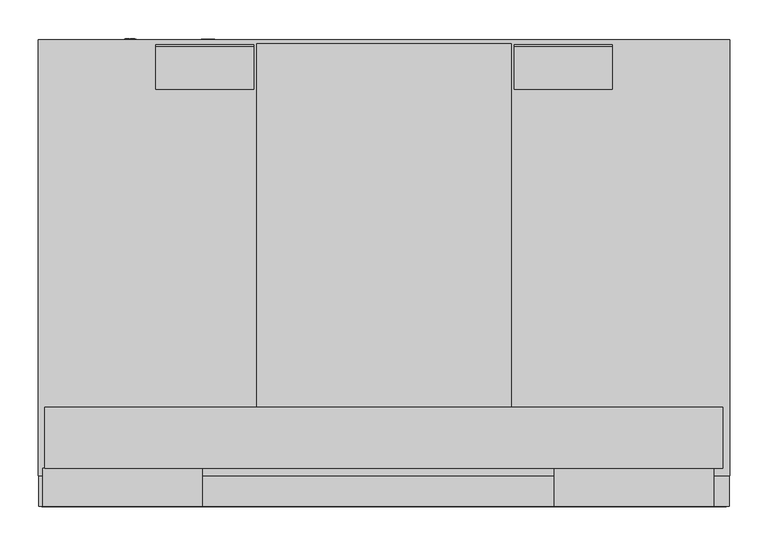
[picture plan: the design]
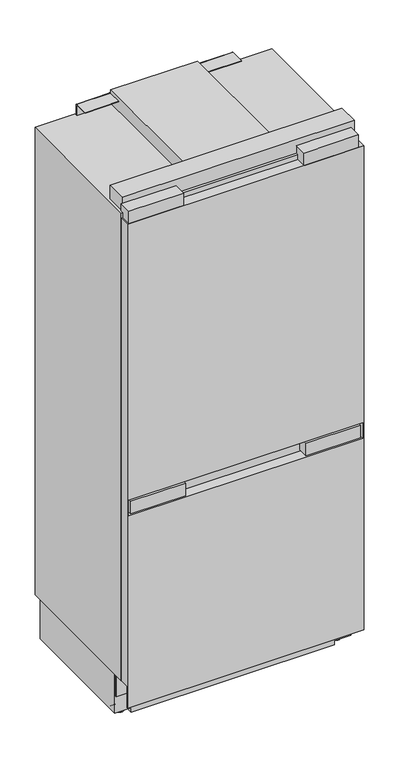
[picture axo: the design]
"""IFC4 building model written with IfcOpenShell, lengths in millimetres: proxy geometry."""

from ifc_helpers import new_model, si_unit, point, frame, frame_2d, origin, place, context, project, spatial, polyline, circle_curve, trimmed, segment, composite_curve, outline, extrude, faceted_brep, source, transform, mapped, element, save
from ifc_brep_helpers import plane_surface, cylinder_surface, advanced_brep


def specialty_equipment_2ae30996(model_context):
    return source(origin(), model_context, "Body", "SolidModel", [
        faceted_brep([(450.5, 19.5805006, 2048.9273907), (450.5, 19.5805006, 100.0958717), (450.5, 22.474204, 100.0958717), (450.5, 22.474204, 187.4499998), (450.5, 95.0, 187.4499998), (450.5, 95.0, 100.0958717), (450.5, 99.0001378, 100.0958717), (450.5, 99.0001378, 2048.9273907), (-450.5, 19.5805006, 2048.9273907), (-450.5, 99.0001378, 2048.9273907), (-450.5, 99.0001378, 100.0958717), (-450.5, 95.0, 100.0958717), (-450.5, 95.0, 187.4499998), (-450.5, 22.474204, 187.4499998), (-450.5, 22.474204, 100.0958717), (-450.5, 19.5805006, 100.0958717), (-446.5, 19.5805006, 934.8801375), (446.5, 19.5805006, 934.8801375), (446.5, 19.5805006, 872.4), (-446.5, 19.5805006, 872.4), (446.5, 93.7083842, 934.8801375), (-446.5, 93.7083842, 934.8801375), (-446.5, 93.7083842, 872.4), (446.5, 93.7083842, 872.4)], [[[0, 1, 2, 3, 4, 5, 6, 7]], [[8, 9, 10, 11, 12, 13, 14, 15]], [[1, 0, 8, 15], [16, 17, 18, 19]], [[1, 15, 14, 2]], [[10, 6, 5, 11]], [[7, 6, 10, 9]], [[0, 7, 9, 8]], [[13, 3, 2, 14]], [[4, 12, 11, 5]], [[3, 13, 12, 4]], [[20, 21, 22, 23]], [[21, 20, 17, 16]], [[22, 21, 16, 19]], [[23, 22, 19, 18]], [[20, 23, 18, 17]]]),
        extrude(outline(polyline([(-229.8997253, 19.5805006), (-437.799475, 19.5805006), (-437.799475, 69.0), (-229.8997253, 69.0), (-229.8997253, 19.5805006)])), frame((0.0, 0.0, 878.4), z_axis=(0.0, 0.0, 1.0), x_axis=(1.0, 0.0, 0.0)), (0.0, 0.0, 1.0), 50.4801375),
        extrude(outline(polyline([(437.799475, 19.5805006), (229.8997253, 19.5805006), (229.8997253, 69.0), (437.799475, 69.0), (437.799475, 19.5805006)])), frame((0.0, 0.0, 878.4), z_axis=(0.0, 0.0, 1.0), x_axis=(1.0, 0.0, 0.0)), (0.0, 0.0, 1.0), 50.4801375),
        extrude(outline(polyline([(-237.4494506, 19.5805006), (-445.3492003, 19.5805006), (-445.3492003, 69.0), (-237.4494506, 69.0), (-237.4494506, 19.5805006)])), frame((0.0, 0.0, 2048.9273907), z_axis=(0.0, 0.0, 1.0), x_axis=(1.0, 0.0, 0.0)), (0.0, 0.0, 1.0), 50.4801375),
        extrude(outline(polyline([(430.2497498, 19.5805006), (222.35, 19.5805006), (222.35, 69.0), (430.2497498, 69.0), (430.2497498, 19.5805006)])), frame((0.0, 0.0, 2048.9273907), z_axis=(0.0, 0.0, 1.0), x_axis=(1.0, 0.0, 0.0)), (0.0, 0.0, 1.0), 50.4801375),
        extrude(outline(composite_curve([segment(trimmed(circle_curve(frame_2d((619.3046941, 2111.8999939)), 2.5), [point((619.3046941, 2114.3999939))], [point((621.8046941, 2111.8999939))], False, "CARTESIAN"), True, "CONTINUOUS"), segment(polyline([(621.8046941, 2111.8999939), (621.8046941, 2068.8999998), (619.3046941, 2068.8999998), (619.3046941, 2112.2000427), (563.7854458, 2112.2000427), (563.7854458, 2114.3999939), (619.3046941, 2114.3999939)]), True, "CONTINUOUS")], self_intersect=False)), frame((170.0666274, 0.0, 0.0), z_axis=(1.0, 0.0, 0.0), x_axis=(0.0, 1.0, 0.0)), (0.0, 0.0, 1.0), 127.807223),
        extrude(outline(composite_curve([segment(trimmed(circle_curve(frame_2d((619.3046941, 2111.8999939)), 2.5), [point((619.3046941, 2114.3999939))], [point((621.8046941, 2111.8999939))], False, "CARTESIAN"), True, "CONTINUOUS"), segment(polyline([(621.8046941, 2111.8999939), (621.8046941, 2068.8999998), (619.3046941, 2068.8999998), (619.3046941, 2112.2000427), (563.7854458, 2112.2000427), (563.7854458, 2114.3999939), (619.3046941, 2114.3999939)]), True, "CONTINUOUS")], self_intersect=False)), frame((-297.8738504, 0.0, 0.0), z_axis=(1.0, 0.0, 0.0), x_axis=(0.0, 1.0, 0.0)), (0.0, 0.0, 1.0), 127.807223),
        faceted_brep([(451.0, 628.6068181, 2068.8999998), (-451.0, 628.6068181, 2068.8999998), (-451.0, 59.5250826, 2068.8999998), (451.0, 59.5250826, 2068.8999998), (451.0, 628.6068181, 187.4499998), (451.0, 59.5250826, 187.4499998), (-451.0, 59.5250826, 187.4499998), (-451.0, 628.6068181, 187.4499998), (-402.0265198, 59.5250826, 1999.0), (402.0265198, 59.5250826, 1999.0), (402.0265198, 59.5250826, 920.0), (-402.0265198, 59.5250826, 920.0), (-402.0265198, 59.5250826, 777.0), (402.0265198, 59.5250826, 777.0), (402.0265198, 59.5250826, 250.0), (-402.0265198, 59.5250826, 250.0), (402.0265198, 551.4500008, 1999.0), (-402.0265198, 551.4500008, 1999.0), (-402.0265198, 551.4500008, 920.0), (402.0265198, 551.4500008, 920.0), (402.0265198, 535.9500008, 777.0), (-402.0265198, 535.9500008, 777.0), (-402.0265198, 535.9500008, 250.0), (402.0265198, 535.9500008, 250.0)], [[[0, 1, 2, 3]], [[4, 5, 6, 7]], [[0, 3, 5, 4]], [[3, 2, 6, 5], [8, 9, 10, 11], [12, 13, 14, 15]], [[2, 1, 7, 6]], [[1, 0, 4, 7]], [[16, 17, 18, 19]], [[17, 16, 9, 8]], [[18, 17, 8, 11]], [[19, 18, 11, 10]], [[16, 19, 10, 9]], [[20, 21, 22, 23]], [[21, 20, 13, 12]], [[22, 21, 12, 15]], [[23, 22, 15, 14]], [[20, 23, 14, 13]]]),
        advanced_brep(
        [(-449.5, 599.2160102, 187.4499998), (449.5, 599.2160102, 187.4499998), (449.5, 599.2160102, 27.500001), (387.3898346, 599.2160102, 27.500001), (387.3898346, 599.2160102, 10.4), (-387.3898346, 599.2160102, 10.4), (-387.3898346, 599.2160102, 27.500001), (-449.5, 599.2160102, 27.500001), (449.5, 104.7548719, 187.4499998), (-449.5, 104.7548719, 187.4499998), (-449.5, 104.7548719, 27.500001), (-387.3898346, 104.7548719, 27.500001), (-387.3898346, 104.7548719, 10.4), (387.3898346, 104.7548719, 10.4), (387.3898346, 104.7548719, 27.500001), (449.5, 104.7548719, 27.500001), (-406.4950732, 165.898232, 25.006546), (-406.4950732, 215.911324, 25.006546), (-406.4950732, 215.7866997, 27.500001), (-406.4950732, 166.0228563, 27.500001), (-406.4950732, 488.6286933, 25.006546), (-406.4950732, 538.6417854, 25.006546), (-406.4950732, 538.517161, 27.500001), (-406.4950732, 488.7533177, 27.500001), (-424.0, 215.911324, 25.006546), (-424.0, 165.898232, 25.006546), (-424.0, 166.0228563, 27.500001), (-424.0, 215.7866997, 27.500001), (-424.0, 538.6417854, 25.006546), (-424.0, 488.6286933, 25.006546), (-424.0, 488.7533177, 27.500001), (-424.0, 538.517161, 27.500001), (424.0, 165.898139, 25.006546), (424.0, 215.911231, 25.006546), (424.0, 215.7866067, 27.500001), (424.0, 166.0227633, 27.500001), (424.0, 488.6286933, 25.006546), (424.0, 538.6417854, 25.006546), (424.0, 538.517161, 27.500001), (424.0, 488.7533177, 27.500001), (406.4950732, 215.911231, 25.006546), (406.4950732, 165.898139, 25.006546), (406.4950732, 166.0227633, 27.500001), (406.4950732, 215.7866067, 27.500001), (406.4950732, 538.6417854, 25.006546), (406.4950732, 488.6286933, 25.006546), (406.4950732, 488.7533177, 27.500001), (406.4950732, 538.517161, 27.500001)],
        [
            (0, 1),
            (1, 2),
            (2, 3),
            (3, 4),
            (4, 5),
            (5, 6),
            (6, 7),
            (7, 0),
            (8, 9),
            (9, 10),
            (10, 11),
            (11, 12),
            (12, 13),
            (13, 14),
            (14, 15),
            (15, 8),
            (0, 9),
            (8, 1),
            (7, 10),
            (4, 13),
            (12, 5),
            (15, 2),
            (16, 17, circle_curve(frame((-406.4950732, 190.904778, 25.006546), z_axis=(1.0, 0.0, 0.0), x_axis=(0.0, 1.0, 0.0)), 25.006546)),
            (17, 18, circle_curve(frame((-406.4950732, 190.904778, 25.006546), z_axis=(1.0, 0.0, 0.0), x_axis=(0.0, 1.0, 0.0)), 25.006546)),
            (18, 19),
            (19, 16, circle_curve(frame((-406.4950732, 190.904778, 25.006546), z_axis=(1.0, 0.0, 0.0), x_axis=(0.0, 1.0, 0.0)), 25.006546)),
            (20, 21, circle_curve(frame((-406.4950732, 513.6352393, 25.006546), z_axis=(1.0, 0.0, 0.0), x_axis=(0.0, 1.0, 0.0)), 25.006546)),
            (21, 22, circle_curve(frame((-406.4950732, 513.6352393, 25.006546), z_axis=(1.0, 0.0, 0.0), x_axis=(0.0, 1.0, 0.0)), 25.006546)),
            (22, 23),
            (23, 20, circle_curve(frame((-406.4950732, 513.6352393, 25.006546), z_axis=(1.0, 0.0, 0.0), x_axis=(0.0, 1.0, 0.0)), 25.006546)),
            (24, 25, circle_curve(frame((-424.0, 190.904778, 25.006546), z_axis=(-1.0, 0.0, 0.0), x_axis=(0.0, 1.0, 0.0)), 25.006546)),
            (25, 26, circle_curve(frame((-424.0, 190.904778, 25.006546), z_axis=(-1.0, 0.0, 0.0), x_axis=(0.0, 1.0, 0.0)), 25.006546)),
            (26, 27),
            (27, 24, circle_curve(frame((-424.0, 190.904778, 25.006546), z_axis=(-1.0, 0.0, 0.0), x_axis=(0.0, 1.0, 0.0)), 25.006546)),
            (28, 29, circle_curve(frame((-424.0, 513.6352393, 25.006546), z_axis=(-1.0, 0.0, 0.0), x_axis=(0.0, 1.0, 0.0)), 25.006546)),
            (29, 30, circle_curve(frame((-424.0, 513.6352393, 25.006546), z_axis=(-1.0, 0.0, 0.0), x_axis=(0.0, 1.0, 0.0)), 25.006546)),
            (30, 31),
            (31, 28, circle_curve(frame((-424.0, 513.6352393, 25.006546), z_axis=(-1.0, 0.0, 0.0), x_axis=(0.0, 1.0, 0.0)), 25.006546)),
            (16, 25),
            (24, 17),
            (20, 29),
            (28, 21),
            (32, 33, circle_curve(frame((424.0, 190.904685, 25.006546), z_axis=(1.0, 0.0, 0.0), x_axis=(0.0, 1.0, 0.0)), 25.006546)),
            (33, 34, circle_curve(frame((424.0, 190.904685, 25.006546), z_axis=(1.0, 0.0, 0.0), x_axis=(0.0, 1.0, 0.0)), 25.006546)),
            (34, 35),
            (35, 32, circle_curve(frame((424.0, 190.904685, 25.006546), z_axis=(1.0, 0.0, 0.0), x_axis=(0.0, 1.0, 0.0)), 25.006546)),
            (36, 37, circle_curve(frame((424.0, 513.6352393, 25.006546), z_axis=(1.0, 0.0, 0.0), x_axis=(0.0, 1.0, 0.0)), 25.006546)),
            (37, 38, circle_curve(frame((424.0, 513.6352393, 25.006546), z_axis=(1.0, 0.0, 0.0), x_axis=(0.0, 1.0, 0.0)), 25.006546)),
            (38, 39),
            (39, 36, circle_curve(frame((424.0, 513.6352393, 25.006546), z_axis=(1.0, 0.0, 0.0), x_axis=(0.0, 1.0, 0.0)), 25.006546)),
            (40, 41, circle_curve(frame((406.4950732, 190.904685, 25.006546), z_axis=(-1.0, 0.0, 0.0), x_axis=(0.0, 1.0, 0.0)), 25.006546)),
            (41, 42, circle_curve(frame((406.4950732, 190.904685, 25.006546), z_axis=(-1.0, 0.0, 0.0), x_axis=(0.0, 1.0, 0.0)), 25.006546)),
            (42, 43),
            (43, 40, circle_curve(frame((406.4950732, 190.904685, 25.006546), z_axis=(-1.0, 0.0, 0.0), x_axis=(0.0, 1.0, 0.0)), 25.006546)),
            (44, 45, circle_curve(frame((406.4950732, 513.6352393, 25.006546), z_axis=(-1.0, 0.0, 0.0), x_axis=(0.0, 1.0, 0.0)), 25.006546)),
            (45, 46, circle_curve(frame((406.4950732, 513.6352393, 25.006546), z_axis=(-1.0, 0.0, 0.0), x_axis=(0.0, 1.0, 0.0)), 25.006546)),
            (46, 47),
            (47, 44, circle_curve(frame((406.4950732, 513.6352393, 25.006546), z_axis=(-1.0, 0.0, 0.0), x_axis=(0.0, 1.0, 0.0)), 25.006546)),
            (32, 41),
            (40, 33),
            (36, 45),
            (44, 37),
            (19, 26),
            (27, 18),
            (23, 30),
            (31, 22),
            (43, 34),
            (35, 42),
            (47, 38),
            (39, 46),
            (11, 6),
            (14, 3),
        ],
        [
            plane_surface(frame((-449.5, 599.2160102, 187.4499998), z_axis=(0.0, 1.0, 0.0), x_axis=(1.0, 0.0, 0.0))),
            plane_surface(frame((-449.5, 104.7548719, 187.4499998), z_axis=(0.0, -1.0, 0.0), x_axis=(-1.0, 0.0, 0.0))),
            plane_surface(frame((449.5, 104.7548719, 187.4499998), z_axis=(0.0, 0.0, 1.0), x_axis=(0.0, 1.0, 0.0))),
            plane_surface(frame((-449.5, 104.7548719, 187.4499998), z_axis=(-1.0, 0.0, 0.0), x_axis=(0.0, 1.0, 0.0))),
            plane_surface(frame((-449.5, 104.7548719, 10.4), z_axis=(0.0, 0.0, -1.0), x_axis=(0.0, 1.0, 0.0))),
            plane_surface(frame((449.5, 104.7548719, 10.4), z_axis=(1.0, 0.0, 0.0), x_axis=(0.0, 1.0, 0.0))),
            plane_surface(frame((-406.4950732, 215.911324, 25.006546), z_axis=(1.0, 0.0, 0.0), x_axis=(0.0, 0.0, 1.0))),
            plane_surface(frame((-424.0, 215.911324, 25.006546), z_axis=(-1.0, 0.0, 0.0), x_axis=(0.0, 0.0, -1.0))),
            cylinder_surface(frame((-424.0, 190.904778, 25.006546), z_axis=(1.0, 0.0, 0.0), x_axis=(0.0, 1.0, 0.0)), 25.006546),
            cylinder_surface(frame((0.0, 513.6352393, 25.006546), z_axis=(1.0, 0.0, 0.0), x_axis=(0.0, 1.0, 0.0)), 25.006546),
            plane_surface(frame((424.0, 215.911231, 25.006546), z_axis=(1.0, 0.0, 0.0), x_axis=(0.0, 0.0, 1.0))),
            plane_surface(frame((406.4950732, 215.911231, 25.006546), z_axis=(-1.0, 0.0, 0.0), x_axis=(0.0, 0.0, -1.0))),
            cylinder_surface(frame((424.0, 190.904685, 25.006546), z_axis=(-1.0, 0.0, 0.0), x_axis=(0.0, 1.0, 0.0)), 25.006546),
            cylinder_surface(frame((0.0, 513.6352393, 25.006546), z_axis=(-1.0, 0.0, 0.0), x_axis=(0.0, 1.0, 0.0)), 25.006546),
            plane_surface(frame((-387.3898346, -429.4357797, 0.0), z_axis=(-1.0, 0.0, 0.0), x_axis=(0.0, 1.0, 0.0))),
            plane_surface(frame((-387.3898346, -429.4357797, 27.500001), z_axis=(0.0, 0.0, -1.0), x_axis=(0.0, 1.0, 0.0))),
            plane_surface(frame((451.0, -429.4357797, 27.500001), z_axis=(0.0, 0.0, -1.0), x_axis=(0.0, 1.0, 0.0))),
            plane_surface(frame((387.3898346, -429.4357797, 27.500001), z_axis=(1.0, 0.0, 0.0), x_axis=(0.0, 1.0, 0.0))),
        ],
        [
            (0, [[1, 2, 3, 4, 5, 6, 7, 8]]),
            (1, [[9, 10, 11, 12, 13, 14, 15, 16]]),
            (2, [[-1, 17, -9, 18]]),
            (3, [[-17, -8, 19, -10]]),
            (4, [[-5, 20, -13, 21]]),
            (5, [[-18, -16, 22, -2]]),
            (6, [[23, 24, 25, 26]]),
            (6, [[27, 28, 29, 30]]),
            (7, [[31, 32, 33, 34]]),
            (7, [[35, 36, 37, 38]]),
            (8, [[-23, 39, -31, 40]]),
            (9, [[-27, 41, -35, 42]]),
            (10, [[43, 44, 45, 46]]),
            (10, [[47, 48, 49, 50]]),
            (11, [[51, 52, 53, 54]]),
            (11, [[55, 56, 57, 58]]),
            (12, [[-43, 59, -51, 60]]),
            (13, [[-47, 61, -55, 62]]),
            (8, [[-39, -26, 63, -32]]),
            (8, [[-40, -34, 64, -24]]),
            (9, [[-41, -30, 65, -36]]),
            (9, [[-42, -38, 66, -28]]),
            (12, [[-60, -54, 67, -44]]),
            (12, [[-59, -46, 68, -52]]),
            (13, [[-62, -58, 69, -48]]),
            (13, [[-61, -50, 70, -56]]),
            (14, [[71, -6, -21, -12]]),
            (15, [[-71, -11, -19, -7], [-25, -64, -33, -63], [-29, -66, -37, -65]]),
            (16, [[72, -3, -22, -15], [-45, -67, -53, -68], [-49, -69, -57, -70]]),
            (17, [[-72, -14, -20, -4]]),
        ],
    ),
        extrude(outline(composite_curve([segment(trimmed(circle_curve(frame_2d((-413.6, 136.7)), 15.0), [point((-428.6, 136.7))], [point((-398.6, 136.7))], False, "CARTESIAN"), True, "CONTINUOUS"), segment(trimmed(circle_curve(frame_2d((-413.6, 136.7)), 15.0), [point((-398.6, 136.7))], [point((-428.6, 136.7))], False, "CARTESIAN"), True, "CONTINUOUS")], self_intersect=False)), frame((0.0, 0.0, 10.4), z_axis=(0.0, 0.0, 1.0), x_axis=(1.0, 0.0, 0.0)), (0.0, 0.0, 1.0), 3.4999939),
        extrude(outline(composite_curve([segment(trimmed(circle_curve(frame_2d((413.6, 136.7)), 15.0), [point((398.6, 136.7))], [point((428.6, 136.7))], False, "CARTESIAN"), True, "CONTINUOUS"), segment(trimmed(circle_curve(frame_2d((413.6, 136.7)), 15.0), [point((428.6, 136.7))], [point((398.6, 136.7))], False, "CARTESIAN"), True, "CONTINUOUS")], self_intersect=False)), frame((0.0, 0.0, 10.4), z_axis=(0.0, 0.0, 1.0), x_axis=(1.0, 0.0, 0.0)), (0.0, 0.0, 1.0), 3.4999939),
        extrude(outline(composite_curve([segment(trimmed(circle_curve(frame_2d((413.6, 136.7)), 10.0), [point((403.6, 136.7))], [point((423.6, 136.7))], False, "CARTESIAN"), True, "CONTINUOUS"), segment(trimmed(circle_curve(frame_2d((413.6, 136.7)), 10.0), [point((423.6, 136.7))], [point((403.6, 136.7))], False, "CARTESIAN"), True, "CONTINUOUS")], self_intersect=False)), frame((0.0, 0.0, 13.8999939), z_axis=(0.0, 0.0, 1.0), x_axis=(1.0, 0.0, 0.0)), (0.0, 0.0, 1.0), 13.6000071),
        extrude(outline(composite_curve([segment(trimmed(circle_curve(frame_2d((-413.6, 136.7)), 10.0), [point((-423.6, 136.7))], [point((-403.6, 136.7))], False, "CARTESIAN"), True, "CONTINUOUS"), segment(trimmed(circle_curve(frame_2d((-413.6, 136.7)), 10.0), [point((-403.6, 136.7))], [point((-423.6, 136.7))], False, "CARTESIAN"), True, "CONTINUOUS")], self_intersect=False)), frame((0.0, 0.0, 13.8999939), z_axis=(0.0, 0.0, 1.0), x_axis=(1.0, 0.0, 0.0)), (0.0, 0.0, 1.0), 13.6000071),
        faceted_brep([(166.0, 623.4547186, 2122.8999939), (-166.0, 623.4547186, 2122.8999939), (-166.0, 149.0, 2122.8999939), (166.0, 149.0, 2122.8999939), (-166.0, 623.4547186, 2068.8999998), (166.0, 623.4547186, 2068.8999998), (166.0, 149.0, 2068.8999998), (442.1341127, 149.0, 2068.8999998), (442.1341127, 69.0, 2068.8999998), (-442.7652816, 69.0, 2068.8999998), (-442.7652816, 149.0, 2068.8999998), (-166.0, 149.0, 2068.8999998), (442.1341127, 69.0, 2124.5509637), (442.1341127, 149.0, 2124.5509637), (-442.7652816, 69.0, 2124.5509637), (-442.7652816, 149.0, 2124.5509637)], [[[0, 1, 2, 3]], [[4, 5, 6, 7, 8, 9, 10, 11]], [[5, 0, 3, 6]], [[1, 0, 5, 4]], [[1, 4, 11, 2]], [[12, 8, 7, 13]], [[14, 15, 10, 9]], [[8, 12, 14, 9]], [[13, 7, 6, 3, 2, 11, 10, 15]], [[12, 13, 15, 14]]]),
        extrude(outline(composite_curve([segment(trimmed(circle_curve(frame_2d((68.8909912, -331.0)), 8.0), [point((68.8909912, -339.0))], [point((68.8909912, -323.0))], False, "CARTESIAN"), True, "CONTINUOUS"), segment(trimmed(circle_curve(frame_2d((68.8909912, -331.0)), 8.0), [point((68.8909912, -323.0))], [point((68.8909912, -339.0))], False, "CARTESIAN"), True, "CONTINUOUS")], self_intersect=False)), frame((0.0, 599.2160102, 0.0), z_axis=(0.0, 1.0, 0.0), x_axis=(0.0, 0.0, 1.0)), (0.0, 0.0, 1.0), 30.0),
        extrude(outline(polyline([(64.7404068, -325.0981918), (72.7769116, -325.0981918), (72.7769116, -330.8744296), (71.7723485, -330.8744296), (71.7723485, -326.1027549), (69.3865111, -326.1027549), (69.3865111, -330.6232888), (68.381948, -330.6232888), (68.381948, -326.1027549), (65.7449699, -326.1027549), (65.7449699, -331.0), (64.7404068, -331.0), (64.7404068, -325.0981918)])), frame((0.0, 629.2160102, 0.0), z_axis=(0.0, 1.0, 0.0), x_axis=(0.0, 0.0, 1.0)), (0.0, 0.0, 1.0), 1.0),
        extrude(outline(polyline([(64.7404068, -332.5068447), (72.7769116, -332.5068447), (72.7769116, -333.5114078), (65.7449699, -333.5114078), (65.7449699, -337.5296602), (64.7404068, -337.5296602), (64.7404068, -332.5068447)])), frame((0.0, 629.2160102, 0.0), z_axis=(0.0, 1.0, 0.0), x_axis=(0.0, 0.0, 1.0)), (0.0, 0.0, 1.0), 1.0),
        extrude(outline(composite_curve([segment(trimmed(circle_curve(frame_2d((38.8909912, -229.0)), 8.0), [point((38.8909912, -237.0))], [point((38.8909912, -221.0))], False, "CARTESIAN"), True, "CONTINUOUS"), segment(trimmed(circle_curve(frame_2d((38.8909912, -229.0)), 8.0), [point((38.8909912, -221.0))], [point((38.8909912, -237.0))], False, "CARTESIAN"), True, "CONTINUOUS")], self_intersect=False)), frame((0.0, 599.2160102, 0.0), z_axis=(0.0, 1.0, 0.0), x_axis=(0.0, 0.0, 1.0)), (0.0, 0.0, 1.0), 30.0),
        extrude(outline(polyline([(35.5144425, -229.9875487), (43.5509473, -227.795953), (43.5509473, -228.8319087), (38.2691429, -230.1033089), (36.6386899, -230.4957164), (38.0807873, -230.9155923), (43.5509473, -232.5087666), (43.5509473, -234.001877), (39.5856699, -235.159479), (36.6386899, -236.0208134), (38.222054, -236.4014486), (43.5509473, -237.682659), (43.5509473, -238.7205767), (35.5144425, -236.5309431), (35.5144425, -235.4557467), (41.7144804, -233.527064), (42.5797389, -233.2582649), (41.5378971, -232.9561111), (35.5144425, -231.2000877), (35.5144425, -229.9875487)])), frame((0.0, 628.6068181, 0.0), z_axis=(0.0, 1.0, 0.0), x_axis=(0.0, 0.0, 1.0)), (0.0, 0.0, 1.0), 1.0),
        extrude(outline(polyline([(35.5144425, -221.1407225), (43.5509473, -221.1407225), (43.5509473, -222.1452856), (39.6170625, -222.1452856), (43.5509473, -226.2655639), (43.5509473, -227.6703826), (40.2468765, -224.2093488), (35.5144425, -227.795953), (35.5144425, -226.5677177), (39.5680116, -223.4971293), (38.2769911, -222.1452856), (35.5144425, -222.1452856), (35.5144425, -221.1407225)])), frame((0.0, 628.6068181, 0.0), z_axis=(0.0, 1.0, 0.0), x_axis=(0.0, 0.0, 1.0)), (0.0, 0.0, 1.0), 1.0),
    ])


if __name__ == "__main__":
    model = new_model("IFC4")
    model_context = context("Model", 3, world=origin())
    ifc_project = project(units=[si_unit("LENGTHUNIT", "METRE", prefix="MILLI")], contexts=[model_context])
    site = spatial("IfcSite", under=ifc_project)
    building = spatial("IfcBuilding", under=site)
    placement = place(None, origin())
    specialty_equipment_shape = specialty_equipment_2ae30996(model_context)
    element("IfcBuildingElementProxy", 1, Name="Specialty Equipment", at=placement, inside=building, context=model_context, shape_type="MappedRepresentation", body=[
        mapped(specialty_equipment_shape, transform((0.0, 0.0, 0.0), x_axis=(1.0, 0.0, 0.0), y_axis=(0.0, 1.0, 0.0), z_axis=(0.0, 0.0, 1.0))),
    ])
    save(model, "model.ifc")
